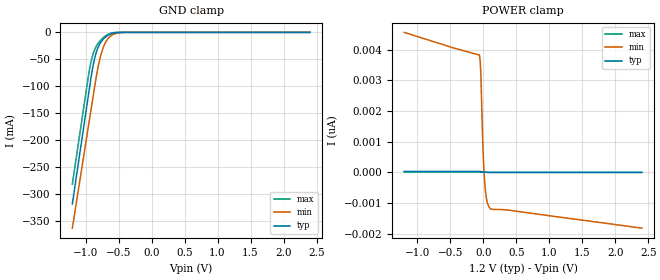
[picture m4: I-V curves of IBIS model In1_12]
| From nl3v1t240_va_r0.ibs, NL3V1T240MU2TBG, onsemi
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|//////////////////////////////////////////////////////////////////////////////
|//////////////////////////////////////////////////////////////////////////////
[Model]  In1_12
Model_type Input
Vinh =  0.84
Vinl =  0.36
|  variable   typ   min   max
C_comp   6.2pF   6.2pF   6.2pF
|//////////////////////////////////////////////////////////////////////////////
[Temperature Range]   25   125   -40
|//////////////////////////////////////////////////////////////////////////////
[Voltage Range]   1.20V   1.10V   1.30V
|//////////////////////////////////////////////////////////////////////////////
[POWER Clamp Reference] 1.20V   1.10V   1.30V
|//////////////////////////////////////////////////////////////////////////////
[GND Clamp Reference]   0V   0V   0V
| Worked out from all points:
|   GND clamp passes 1 mA (typ) near -0.56 V on its own axis
|//////////////////////////////////////////////////////////////////////////////
[GND Clamp]
|   Voltage   I(typ)   I(min)   I(max)
-1.2V     -318.7mA   -363.4mA   -282mA
-960mV    -119.4mA   -177.1mA   -83.84mA
-940mV    -102.8mA   -161.6mA   -69.07mA
-900mV    -71.2mA    -130.5mA   -46.37mA
-840mV    -38.28mA   -84.25mA   -26.43mA
-800mV    -25.17mA   -58.4mA    -18.78mA
-760mV    -16.85mA   -38.63mA   -13.12mA
-700mV    -9.037mA   -19.28mA   -6.774mA
-620mV    -3.033mA   -6.913mA   -1.801mA
-520mV    -307.5uA   -1.373mA   -95.74uA
-400mV    -4.681uA   -69.73uA   -655.5nA
2.4V      -8.2pA     -741.9pA   295.3fA
|//////////////////////////////////////////////////////////////////////////////
[POWER Clamp]
|   Voltage   I(typ)   I(min)   I(max)
-1.2V     26.79pA    4.56nA     366.4fA
-60mV     24.69pA    3.819nA    -443.2fA
-50mV     22.92pA    3.653nA    -450.3fA
-40mV     20.39pA    3.239nA    -457.4fA
-10mV     10.81pA    961.7pA    -478.7fA
0V        7.579pA    411.5pA    -485.8fA
20mV      1.714pA    -336.9pA   -500fA
30mV      -662.3fA   -600pA     -507.1fA
50mV      -4.24pA    -908.4pA   -521.3fA
80mV      -6.995pA   -1.116nA   -542.6fA
110mV     -7.838pA   -1.194nA   -563.9fA
2.4V      -9.735pA   -1.823nA   -2.19pA
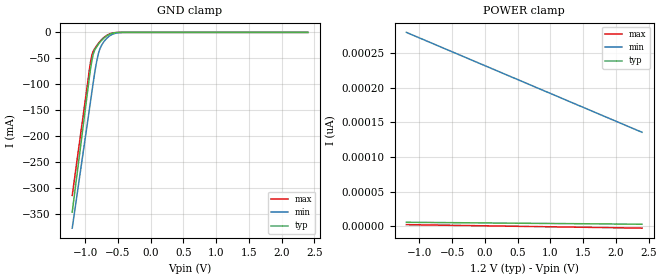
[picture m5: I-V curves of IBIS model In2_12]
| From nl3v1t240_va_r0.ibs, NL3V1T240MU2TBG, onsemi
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|//////////////////////////////////////////////////////////////////////////////
|//////////////////////////////////////////////////////////////////////////////
[Model]  In2_12
Model_type Input
Vinh =  0.84
Vinl =  0.36
|  variable   typ   min   max
C_comp   4.8pF   4.8pF   4.8pF
|//////////////////////////////////////////////////////////////////////////////
[Temperature Range]   25   125   -40
|//////////////////////////////////////////////////////////////////////////////
[Voltage Range]   1.20V   1.10V   1.30V
|//////////////////////////////////////////////////////////////////////////////
[POWER Clamp Reference] 1.20V   1.10V   1.30V
|//////////////////////////////////////////////////////////////////////////////
[GND Clamp Reference]   0V   0V   0V
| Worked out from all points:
|   GND clamp passes 1 mA (typ) near -0.56 V on its own axis
|//////////////////////////////////////////////////////////////////////////////
[GND Clamp]
|   Voltage   I(typ)   I(min)   I(max)
-1.2V     -346.3mA   -377.1mA   -314mA
-940mV    -88.24mA   -150mA     -73.73mA
-900mV    -54.32mA   -115.1mA   -44.15mA
-880mV    -42.51mA   -97.64mA   -36.66mA
-860mV    -35.19mA   -80.63mA   -32.16mA
-820mV    -26.61mA   -51.9mA    -24.64mA
-800mV    -22.96mA   -40.82mA   -21.17mA
-740mV    -13.75mA   -22.38mA   -12.56mA
-660mV    -5.672mA   -9.946mA   -4.966mA
-560mV    -947.3uA   -2.507mA   -706.6uA
-420mV    -10.83uA   -97.89uA   -5.741uA
2.4V      5.63pA     284.2pA    2.062pA
|//////////////////////////////////////////////////////////////////////////////
[POWER Clamp]
|   Voltage   I(typ)   I(min)   I(max)
-1.2V     5.63pA     280.2pA    2.202pA
0V        4.688pA    232pA      525.4fA
1.2V      3.745pA    183.9pA    -1.151pA
2.4V      2.803pA    135.8pA    -2.828pA
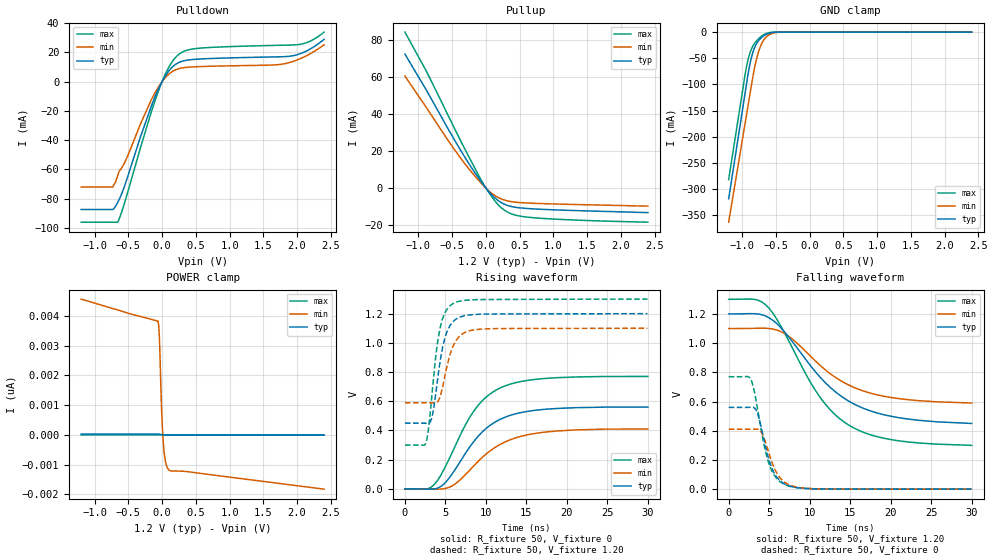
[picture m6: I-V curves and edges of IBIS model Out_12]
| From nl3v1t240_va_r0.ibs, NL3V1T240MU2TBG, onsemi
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|//////////////////////////////////////////////////////////////////////////////
|//////////////////////////////////////////////////////////////////////////////
[Model] Out_12
Model_type 3-state
Polarity Inverting
Enable Active-Low
Vmeas = 0.6
Vref = 1.2
Rref = 2k
Cref = 15pF
|  variable   typ   min   max
C_comp   5.9pF   5.9pF   5.9pF
|//////////////////////////////////////////////////////////////////////////////
[Temperature Range]   25   125   -40
|//////////////////////////////////////////////////////////////////////////////
[Voltage Range]   1.20V   1.10V   1.30V
|//////////////////////////////////////////////////////////////////////////////
[Pulldown Reference]   0V   0V   0V
|//////////////////////////////////////////////////////////////////////////////
[Pullup Reference]   1.20V   1.10V   1.30V
|//////////////////////////////////////////////////////////////////////////////
[GND Clamp Reference]   0V   0V   0V
|//////////////////////////////////////////////////////////////////////////////
[POWER Clamp Reference] 1.20V   1.10V   1.30V
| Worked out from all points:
|   slope of the pulldown table from 0 to 0.18 V, typ, clamps not added: 16.2 ohm
|   slope of the pullup table from 0 to 0.18 V, typ, clamps not added: 26.9 ohm
|   GND clamp passes 1 mA (typ) near -0.56 V on its own axis
|   falling waveform, R_fixture 50, V_fixture 1.20: 20-80 % time 7.63ns typ, 7.21ns min, 6.75ns max; typ from 1.2 V to 0.45 V
|   falling waveform, R_fixture 50, V_fixture 0: 20-80 % time 1.69ns typ, 1.77ns min, 1.76ns max; typ from 0.56 V to 0 V
|   rising waveform, R_fixture 50, V_fixture 0: 20-80 % time 4.92ns typ, 5.45ns min, 4.78ns max; typ from 0 V to 0.56 V
|   rising waveform, R_fixture 50, V_fixture 1.20: 20-80 % time 1.36ns typ, 1.5ns min, 1.26ns max; typ from 0.45 V to 1.2 V
|//////////////////////////////////////////////////////////////////////////////
[Pulldown]
|   Voltage   I(typ)   I(min)   I(max)
-1.2V     -87.41mA   -72.09mA   -96.08mA
-730mV    -87.41mA   -72.09mA   -96.08mA
-650mV    -81.85mA   -63.15mA   -95.35mA
-540mV    -69.07mA   -53.8mA    -80.31mA
-320mV    -37.64mA   -28.83mA   -45.04mA
-100mV    -9.841mA   -7.212mA   -12.32mA
80mV      6.064mA    4.222mA    8.144mA
240mV     12.83mA    8.647mA    18.27mA
560mV     15.37mA    10.18mA    22.77mA
1.77V     16.92mA    11.8mA     24.76mA
2.13V     20.64mA    17.39mA    26.37mA
2.4V      28.8mA     25.07mA    33.75mA
|//////////////////////////////////////////////////////////////////////////////
[Pullup]
|   Voltage   I(typ)   I(min)   I(max)
-1.2V     72.38mA    60.55mA    84.3mA
-880mV    52.83mA    43.38mA    63.02mA
-550mV    31.34mA    25.21mA    38.52mA
-280mV    14.85mA    11.69mA    18.83mA
-100mV    4.991mA    3.89mA     6.334mA
0V        8.022uA    5.575uA    19.24uA
120mV     -4.891mA   -3.724mA   -6.292mA
240mV     -8.095mA   -6.041mA   -11mA
400mV     -10.15mA   -7.447mA   -14.22mA
660mV     -11.15mA   -8.14mA    -15.88mA
1.37V     -12.21mA   -8.924mA   -17.35mA
2.4V      -13.25mA   -9.76mA    -18.44mA
|//////////////////////////////////////////////////////////////////////////////
[GND Clamp]
|   Voltage   I(typ)   I(min)   I(max)
-1.2V     -318.7mA   -363.4mA   -282mA
-960mV    -119.4mA   -177.1mA   -83.84mA
-940mV    -102.8mA   -161.6mA   -69.07mA
-900mV    -71.2mA    -130.5mA   -46.37mA
-840mV    -38.28mA   -84.25mA   -26.43mA
-800mV    -25.17mA   -58.4mA    -18.78mA
-760mV    -16.85mA   -38.63mA   -13.12mA
-700mV    -9.037mA   -19.28mA   -6.774mA
-620mV    -3.033mA   -6.913mA   -1.801mA
-520mV    -307.5uA   -1.373mA   -95.74uA
-400mV    -4.681uA   -69.73uA   -655.5nA
2.4V      -8.2pA     -741.9pA   295.3fA
|//////////////////////////////////////////////////////////////////////////////
[POWER Clamp]
|   Voltage   I(typ)   I(min)   I(max)
-1.2V     26.79pA    4.56nA     366.4fA
-60mV     24.69pA    3.819nA    -443.2fA
-50mV     22.92pA    3.653nA    -450.3fA
-40mV     20.39pA    3.239nA    -457.4fA
-10mV     10.81pA    961.7pA    -478.7fA
0V        7.579pA    411.5pA    -485.8fA
20mV      1.714pA    -336.9pA   -500fA
30mV      -662.3fA   -600pA     -507.1fA
50mV      -4.24pA    -908.4pA   -521.3fA
80mV      -6.995pA   -1.116nA   -542.6fA
110mV     -7.838pA   -1.194nA   -563.9fA
2.4V      -9.735pA   -1.823nA   -2.19pA
|//////////////////////////////////////////////////////////////////////////////
|//////////////////////////////////////////////////////////////////////////////
[Ramp]
|  variable   typ   min   max
dV/dt_r   3.360E-01/4.950E-09  2.460E-01/5.550E-09  4.620E-01/4.800E-09
dV/dt_f   4.500E-01/7.600E-09  3.060E-01/7.200E-09  6.000E-01/6.600E-09
R_load = 50
|//////////////////////////////////////////////////////////////////////////////
[Falling Waveform]
R_fixture = 50
V_fixture = 1.20
V_fixture_min = 1.10
V_fixture_max = 1.30
C_fixture = 0p
|   time   V(typ)   V(min)   V(max)
0s        1.2V       1.1V       1.3V
3.2ns     1.201V     1.101V     1.3V
4.8ns     1.179V     1.101V     1.25V
7.2ns     1.057V     1.055V     1.039V
11ns      785.3mV    862.9mV    652.4mV
12.8ns    684.6mV    780.5mV    528.9mV
14.8ns    604.1mV    713.9mV    440.1mV
17.2ns    541.9mV    662.7mV    378.3mV
20.15ns   498mV      626.9mV    338.5mV
30ns      450mV      590mV      300mV
|//////////////////////////////////////////////////////////////////////////////
[Falling Waveform]
R_fixture = 50
V_fixture = 0
C_fixture = 0p
|   time   V(typ)   V(min)   V(max)
0s        560mV      410mV      770mV
2.7ns     560.8mV    410mV      754.7mV
3.1ns     558.9mV    410.5mV    685.6mV
3.6ns     513.5mV    410.2mV    539.6mV
4.2ns     378.6mV    373.5mV    349.8mV
4.9ns     215.5mV    259.1mV    187.4mV
5.8ns     93.78mV    125.1mV    82.49mV
6.9ns     35.55mV    48.27mV    32.77mV
10.5ns    2.628mV    3.42mV     2.699mV
30ns      0V         0V         0V
|//////////////////////////////////////////////////////////////////////////////
[Rising Waveform]
R_fixture = 50
V_fixture = 0
C_fixture = 0p
|   time   V(typ)   V(min)   V(max)
0s        0V         0V         0V
2.7ns     -1.551mV   -625.2uV   -50.82uV
3.6ns     -802.5uV   -1.563mV   29.01mV
5.25ns    59.36mV    6.816mV    181.5mV
6.45ns    154.1mV    44.54mV    322.7mV
8.4ns     316.9mV    151.3mV    523.7mV
10.05ns   414.7mV    239.5mV    629.4mV
11.85ns   478.4mV    307mV      693.1mV
17.15ns   544.3mV    387.9mV    755.6mV
30ns      560mV      410mV      770mV
|//////////////////////////////////////////////////////////////////////////////
[Rising Waveform]
R_fixture = 50
V_fixture = 1.20
V_fixture_min = 1.10
V_fixture_max = 1.30
C_fixture = 0p
|   time   V(typ)   V(min)   V(max)
0s        450mV      590mV      300mV
2.6ns     449.5mV    590mV      316mV
2.9ns     448.6mV    590mV      407.8mV
3.4ns     506.4mV    589.5mV    681.8mV
4.3ns     855.7mV    624.8mV    1.089V
5ns       1.045V     789.3mV    1.212V
5.9ns     1.143V     971.2mV    1.267V
7.1ns     1.182V     1.061V     1.289V
9.1ns     1.196V     1.093V     1.296V
29.95ns   1.2V       1.1V       1.3V
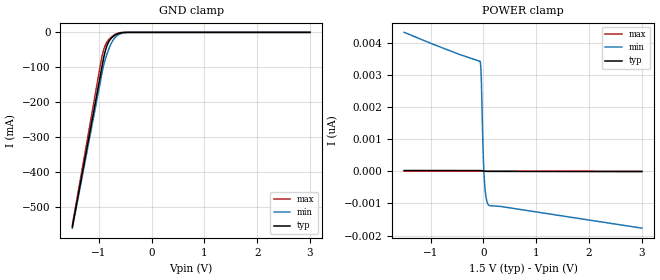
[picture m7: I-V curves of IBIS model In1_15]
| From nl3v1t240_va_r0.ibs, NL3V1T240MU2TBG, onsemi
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|//////////////////////////////////////////////////////////////////////////////
|//////////////////////////////////////////////////////////////////////////////
[Model]  In1_15
Model_type Input
Vinh =  1.05
Vinl =  0.45
|  variable   typ   min   max
C_comp   6.2pF   6.2pF   6.2pF
|//////////////////////////////////////////////////////////////////////////////
[Temperature Range]   25   125   -40
|//////////////////////////////////////////////////////////////////////////////
[Voltage Range]   1.50V   1.40V   1.60V
|//////////////////////////////////////////////////////////////////////////////
[POWER Clamp Reference] 1.50V   1.40V   1.60V
|//////////////////////////////////////////////////////////////////////////////
[GND Clamp Reference]   0V   0V   0V
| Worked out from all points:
|   GND clamp passes 1 mA (typ) near -0.57 V on its own axis
|//////////////////////////////////////////////////////////////////////////////
[GND Clamp]
|   Voltage   I(typ)   I(min)   I(max)
-1.5V     -557.7mA   -561.1mA   -552.3mA
-960mV    -115.9mA   -134.5mA   -85.51mA
-940mV    -99.49mA   -118.7mA   -70.19mA
-900mV    -68.21mA   -89.65mA   -46.72mA
-860mV    -44.98mA   -69.53mA   -31.68mA
-800mV    -24.14mA   -44mA      -18.84mA
-740mV    -13.37mA   -25.16mA   -10.78mA
-680mV    -6.942mA   -13.11mA   -5.168mA
-620mV    -2.923mA   -6.276mA   -1.797mA
-460mV    -38.74uA   -327.3uA   -8.324uA
3V        -107.2fA   -626.2pA   1.119pA
|//////////////////////////////////////////////////////////////////////////////
[POWER Clamp]
|   Voltage   I(typ)   I(min)   I(max)
-1.5V     21.77pA    4.316nA    1.167pA
-60mV     19.08pA    3.413nA    484.2fA
-50mV     18.75pA    3.259nA    479.4fA
-40mV     17.79pA    2.878nA    474.7fA
-10mV     10.26pA    822.4pA    460.4fA
0V        7.334pA    334.5pA    455.7fA
10mV      4.593pA    -46.06pA   451fA
20mV      2.157pA    -327pA     446.2fA
30mV      85.95fA    -556.4pA   441.5fA
50mV      -2.83pA    -815.8pA   432fA
100mV     -4.914pA   -1.057nA   408.3fA
3V        -13.66pA   -1.77nA    -966.4fA
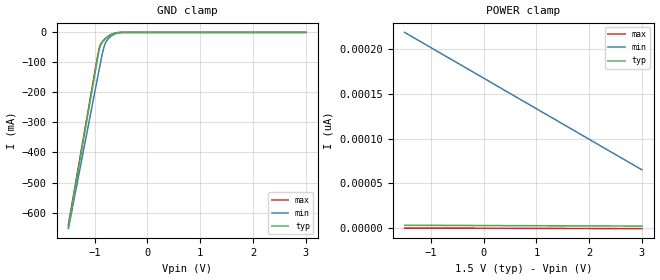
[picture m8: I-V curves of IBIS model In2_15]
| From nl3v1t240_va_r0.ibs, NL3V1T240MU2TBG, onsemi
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|//////////////////////////////////////////////////////////////////////////////
|//////////////////////////////////////////////////////////////////////////////
[Model]  In2_15
Model_type Input
Vinh =  1.05
Vinl =  0.45
|  variable   typ   min   max
C_comp   4.8pF   4.8pF   4.8pF
|//////////////////////////////////////////////////////////////////////////////
[Temperature Range]   25   125   -40
|//////////////////////////////////////////////////////////////////////////////
[Voltage Range]   1.50V   1.40V   1.60V
|//////////////////////////////////////////////////////////////////////////////
[POWER Clamp Reference] 1.50V   1.40V   1.60V
|//////////////////////////////////////////////////////////////////////////////
[GND Clamp Reference]   0V   0V   0V
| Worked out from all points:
|   GND clamp passes 1 mA (typ) near -0.57 V on its own axis
|//////////////////////////////////////////////////////////////////////////////
[GND Clamp]
|   Voltage   I(typ)   I(min)   I(max)
-1.5V     -647.1mA   -653.7mA   -640.7mA
-960mV    -99.94mA   -163.4mA   -92.65mA
-920mV    -62.15mA   -127.1mA   -55.93mA
-900mV    -47.82mA   -108.9mA   -43.57mA
-880mV    -38.63mA   -90.77mA   -36.45mA
-840mV    -29.17mA   -58.76mA   -28.07mA
-800mV    -21.77mA   -36.39mA   -20.87mA
-760mV    -15.56mA   -24.65mA   -14.88mA
-640mV    -3.867mA   -7.053mA   -3.566mA
-460mV    -31.96uA   -229.2uA   -24.55uA
3V        3.178pA    222.1pA    38.72fA
|//////////////////////////////////////////////////////////////////////////////
[POWER Clamp]
|   Voltage   I(typ)   I(min)   I(max)
-1.5V     3.178pA    218.7pA    53.57fA
0V        2.87pA     167.5pA    -169.2fA
1.5V      2.562pA    116.3pA    -392fA
3V        2.255pA    65.13pA    -614.8fA
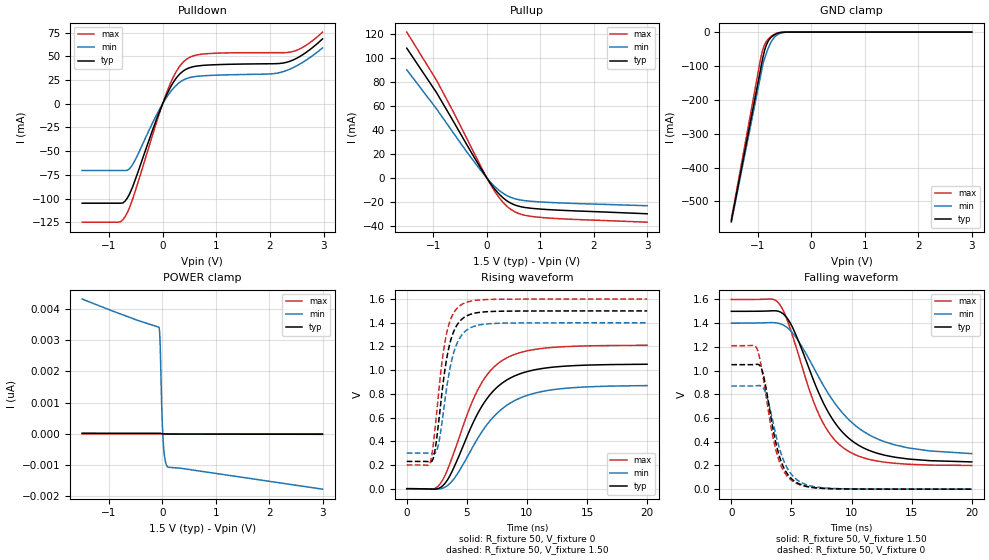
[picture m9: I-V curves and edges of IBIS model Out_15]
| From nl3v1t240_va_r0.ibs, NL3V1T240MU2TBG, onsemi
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|//////////////////////////////////////////////////////////////////////////////
|//////////////////////////////////////////////////////////////////////////////
[Model] Out_15
Model_type 3-state
Polarity Inverting
Enable Active-Low
Vmeas = 0.75
Vref = 1.5
Rref = 2k
Cref = 15pF
|  variable   typ   min   max
C_comp   5.9pF   5.9pF   5.9pF
|//////////////////////////////////////////////////////////////////////////////
[Temperature Range]   25   125   -40
|//////////////////////////////////////////////////////////////////////////////
[Voltage Range]   1.50V   1.40V   1.60V
|//////////////////////////////////////////////////////////////////////////////
[Pulldown Reference]   0V   0V   0V
|//////////////////////////////////////////////////////////////////////////////
[Pullup Reference]   1.50V   1.40V   1.60V
|//////////////////////////////////////////////////////////////////////////////
[GND Clamp Reference]   0V   0V   0V
|//////////////////////////////////////////////////////////////////////////////
[POWER Clamp Reference] 1.50V   1.40V   1.60V
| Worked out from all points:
|   slope of the pulldown table from 0 to 0.225 V, typ, clamps not added: 9.08 ohm
|   slope of the pullup table from 0 to 0.225 V, typ, clamps not added: 17 ohm
|   GND clamp passes 1 mA (typ) near -0.57 V on its own axis
|   falling waveform, R_fixture 50, V_fixture 1.50: 20-80 % time 3.62ns typ, 4.53ns min, 3.09ns max; typ from 1.5 V to 0.23 V
|   falling waveform, R_fixture 50, V_fixture 0: 20-80 % time 1.33ns typ, 1.5ns min, 1.36ns max; typ from 1.05 V to 0 V
|   rising waveform, R_fixture 50, V_fixture 0: 20-80 % time 3.29ns typ, 3.71ns min, 3.04ns max; typ from 0 V to 1.05 V
|   rising waveform, R_fixture 50, V_fixture 1.50: 20-80 % time 1.08ns typ, 1.13ns min, 1.01ns max; typ from 0.23 V to 1.5 V
|//////////////////////////////////////////////////////////////////////////////
[Pulldown]
|   Voltage   I(typ)   I(min)   I(max)
-1.5V     -104.7mA   -70.31mA   -124.7mA
-820mV    -104.7mA   -70.31mA   -124.7mA
-700mV    -102.6mA   -70.31mA   -119mA
-560mV    -87.62mA   -64.15mA   -100.5mA
-100mV    -14.22mA   -10.23mA   -16.98mA
90mV      11.26mA    8.129mA    13.93mA
270mV     28.22mA    20.34mA    35.49mA
420mV     35.82mA    25.95mA    45.78mA
810mV     40.64mA    29.63mA    52.67mA
2.28V     43.27mA    34.47mA    53.82mA
2.58V     50.58mA    42.58mA    58.51mA
2.98V     68.35mA    58.85mA    75.48mA
|//////////////////////////////////////////////////////////////////////////////
[Pullup]
|   Voltage   I(typ)   I(min)   I(max)
-1.5V     108.2mA    90.16mA    121.6mA
-940mV    70.95mA    57.42mA    81.26mA
-630mV    47.38mA    37.72mA    55.25mA
-300mV    21.93mA    17.15mA    26.13mA
40mV      -2.764mA   -2.134mA   -3.163mA
220mV     -13.02mA   -10.05mA   -15.9mA
320mV     -17.24mA   -13.26mA   -21.19mA
410mV     -20.09mA   -15.45mA   -24.92mA
510mV     -22.31mA   -17.15mA   -27.9mA
620mV     -23.83mA   -18.32mA   -30.02mA
930mV     -25.71mA   -19.81mA   -32.59mA
3V        -29.87mA   -23.17mA   -36.9mA
|//////////////////////////////////////////////////////////////////////////////
[GND Clamp]
|   Voltage   I(typ)   I(min)   I(max)
-1.5V     -557.7mA   -561.1mA   -552.3mA
-960mV    -115.9mA   -134.5mA   -85.51mA
-940mV    -99.49mA   -118.7mA   -70.19mA
-900mV    -68.21mA   -89.65mA   -46.72mA
-860mV    -44.98mA   -69.53mA   -31.68mA
-800mV    -24.14mA   -44mA      -18.84mA
-740mV    -13.37mA   -25.16mA   -10.78mA
-680mV    -6.942mA   -13.11mA   -5.168mA
-620mV    -2.923mA   -6.276mA   -1.797mA
-460mV    -38.74uA   -327.3uA   -8.324uA
3V        -107.2fA   -626.2pA   1.119pA
|//////////////////////////////////////////////////////////////////////////////
[POWER Clamp]
|   Voltage   I(typ)   I(min)   I(max)
-1.5V     21.77pA    4.316nA    1.167pA
-60mV     19.08pA    3.413nA    484.2fA
-50mV     18.75pA    3.259nA    479.4fA
-40mV     17.79pA    2.878nA    474.7fA
-10mV     10.26pA    822.4pA    460.4fA
0V        7.334pA    334.5pA    455.7fA
10mV      4.593pA    -46.06pA   451fA
20mV      2.157pA    -327pA     446.2fA
30mV      85.95fA    -556.4pA   441.5fA
50mV      -2.83pA    -815.8pA   432fA
100mV     -4.914pA   -1.057nA   408.3fA
3V        -13.66pA   -1.77nA    -966.4fA
|//////////////////////////////////////////////////////////////////////////////
|//////////////////////////////////////////////////////////////////////////////
[Ramp]
|  variable   typ   min   max
dV/dt_r   6.300E-01/3.250E-09  5.220E-01/3.625E-09  7.260E-01/3.000E-09
dV/dt_f   7.620E-01/3.700E-09  6.600E-01/4.500E-09  8.400E-01/3.100E-09
R_load = 50
|//////////////////////////////////////////////////////////////////////////////
[Falling Waveform]
R_fixture = 50
V_fixture = 1.50
V_fixture_min = 1.40
V_fixture_max = 1.60
C_fixture = 0p
|   time   V(typ)   V(min)   V(max)
0s        1.5V       1.4V       1.6V
3.3ns     1.504V     1.405V     1.603V
4ns       1.497V     1.397V     1.561V
5.1ns     1.362V     1.317V     1.291V
7.3ns     805.5mV    939.5mV    626.9mV
8.3ns     609mV      770.2mV    452.3mV
9.5ns     454.5mV    614.9mV    335.6mV
11.3ns    333.8mV    467.8mV    255.9mV
13.58ns   269.9mV    374.1mV    218.5mV
20ns      230mV      300mV      200mV
|//////////////////////////////////////////////////////////////////////////////
[Falling Waveform]
R_fixture = 50
V_fixture = 0
C_fixture = 0p
|   time   V(typ)   V(min)   V(max)
0s        1.05V      870mV      1.21V
2.1ns     1.053V     871.9mV    1.192V
2.4ns     1.039V     873mV      1.085V
2.7ns     948mV      847.3mV    908.7mV
3.3ns     604.1mV    641.2mV    524.6mV
3.8ns     350.1mV    419mV      294.7mV
4.4ns     173.4mV    230mV      145.6mV
5.2ns     71.11mV    102.3mV    60.83mV
8ns       5.333mV    8.714mV    4.802mV
20ns      0V         0V         0V
|//////////////////////////////////////////////////////////////////////////////
[Rising Waveform]
R_fixture = 50
V_fixture = 0
C_fixture = 0p
|   time   V(typ)   V(min)   V(max)
0s        0V         0V         0V
2.125ns   -3.906mV   -3.482mV   -2.481mV
2.75ns    7.306mV    -1.388mV   37.35mV
3.875ns   168.2mV    76.61mV    290.9mV
5.875ns   628.9mV    419.7mV    827.3mV
6.875ns   786.5mV    566.1mV    985.3mV
8.125ns   904.3mV    689.2mV    1.093V
9.75ns    980.4mV    777.7mV    1.157V
12ns      1.024V     832.9mV    1.191V
20ns      1.05V      870mV      1.21V
|//////////////////////////////////////////////////////////////////////////////
[Rising Waveform]
R_fixture = 50
V_fixture = 1.50
V_fixture_min = 1.40
V_fixture_max = 1.60
C_fixture = 0p
|   time   V(typ)   V(min)   V(max)
0s        230mV      300mV      200mV
1.95ns    226mV      298.9mV    220.5mV
2.25ns    273.2mV    295.5mV    408.2mV
2.6ns     514.6mV    356.4mV    754.4mV
2.95ns    828.2mV    572.4mV    1.083V
3.25ns    1.053V     800.5mV    1.278V
3.8ns     1.298V     1.108V     1.464V
4.5ns     1.422V     1.285V     1.55V
6.8ns     1.494V     1.391V     1.596V
20ns      1.5V       1.4V       1.6V
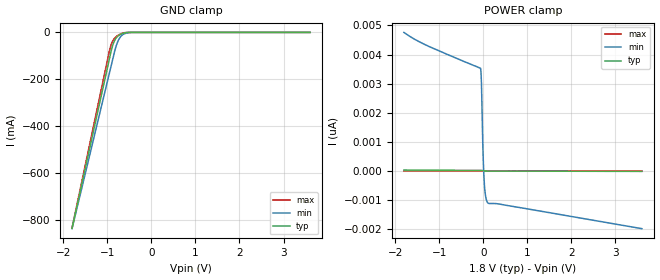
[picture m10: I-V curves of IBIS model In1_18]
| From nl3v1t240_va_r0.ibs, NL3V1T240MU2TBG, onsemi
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|//////////////////////////////////////////////////////////////////////////////
|//////////////////////////////////////////////////////////////////////////////
[Model]  In1_18
Model_type Input
Vinh =  1.17
Vinl =  0.63
|  variable   typ   min   max
C_comp   6.2pF   6.2pF   6.2pF
|//////////////////////////////////////////////////////////////////////////////
[Temperature Range]   25   125   -40
|//////////////////////////////////////////////////////////////////////////////
[Voltage Range]   1.80V   1.65V   1.95V
|//////////////////////////////////////////////////////////////////////////////
[POWER Clamp Reference] 1.80V   1.65V   1.95V
|//////////////////////////////////////////////////////////////////////////////
[GND Clamp Reference]   0V   0V   0V
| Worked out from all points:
|   GND clamp passes 1 mA (typ) near -0.57 V on its own axis
|//////////////////////////////////////////////////////////////////////////////
[GND Clamp]
|   Voltage   I(typ)   I(min)   I(max)
-1.8V     -834.6mA   -836.2mA   -832.7mA
-960mV    -119.4mA   -179.5mA   -85.23mA
-920mV    -85.38mA   -148.3mA   -56.63mA
-880mV    -56.94mA   -117mA     -37.69mA
-840mV    -37.08mA   -85.74mA   -26.12mA
-800mV    -24.33mA   -58.65mA   -18.59mA
-740mV    -13.37mA   -30.44mA   -10.6mA
-680mV    -6.897mA   -14.63mA   -5.041mA
-600mV    -2.006mA   -5.032mA   -1.087mA
-480mV    -76.25uA   -545.6uA   -17.52uA
3.6V      182.4fA    -559.8pA   2.202pA
|//////////////////////////////////////////////////////////////////////////////
[POWER Clamp]
|   Voltage   I(typ)   I(min)   I(max)
-1.8V     30.61pA    4.763nA    2.297pA
-1.24V    24.24pA    4.285nA    1.941pA
-60mV     16.09pA    3.529nA    1.191pA
-50mV     16.02pA    3.381nA    1.184pA
-40mV     15.63pA    3.007nA    1.178pA
-10mV     9.965pA    918.7pA    1.159pA
0V        7.063pA    402.9pA    1.152pA
20mV      1.834pA    -305.7pA   1.14pA
40mV      -2.197pA   -716.1pA   1.127pA
60mV      -4.533pA   -920.1pA   1.114pA
110mV     -6.235pA   -1.11nA    1.082pA
3.6V      -17.98pA   -1.988nA   -1.138pA
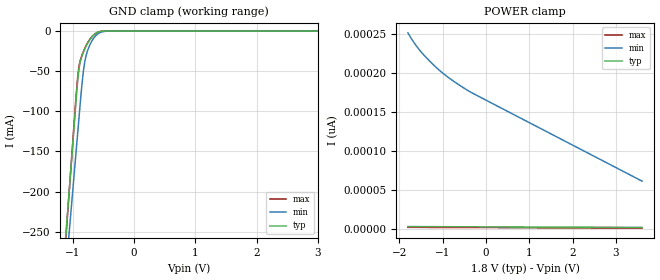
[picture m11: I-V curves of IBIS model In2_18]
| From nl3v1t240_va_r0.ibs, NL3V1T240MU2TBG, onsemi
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|//////////////////////////////////////////////////////////////////////////////
|//////////////////////////////////////////////////////////////////////////////
[Model]  In2_18
Model_type Input
Vinh =  1.17
Vinl =  0.63
|  variable   typ   min   max
C_comp   4.8pF   4.8pF   4.8pF
|//////////////////////////////////////////////////////////////////////////////
[Temperature Range]   25   125   -40
|//////////////////////////////////////////////////////////////////////////////
[Voltage Range]   1.80V   1.65V   1.95V
|//////////////////////////////////////////////////////////////////////////////
[POWER Clamp Reference] 1.80V   1.65V   1.95V
|//////////////////////////////////////////////////////////////////////////////
[GND Clamp Reference]   0V   0V   0V
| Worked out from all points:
|   GND clamp passes 1 mA (typ) near -0.57 V on its own axis
|//////////////////////////////////////////////////////////////////////////////
[GND Clamp]
|   Voltage   I(typ)   I(min)   I(max)
-1.8V     -949.2mA   -914.6mA   -991.5mA
-1.12V    -262.6mA   -306.9mA   -267.3mA
-1.06V    -202mA     -253.3mA   -203.4mA
-1.02V    -161.6mA   -217.5mA   -160.8mA
-940mV    -80.86mA   -146mA     -76.23mA
-900mV    -48.04mA   -110.3mA   -45.09mA
-840mV    -29.12mA   -59.69mA   -28.4mA
-800mV    -21.61mA   -36.85mA   -21.05mA
-720mV    -10.48mA   -17.13mA   -10.19mA
-620mV    -2.719mA   -5.469mA   -2.574mA
-400mV    -3.034uA   -39.27uA   -2.45uA
3.6V      3.12pA     221.3pA    2.156pA
|//////////////////////////////////////////////////////////////////////////////
[POWER Clamp]
|   Voltage   I(typ)   I(min)   I(max)
-1.8V     3.12pA     251.3pA    2.186pA
-1.68V    3.097pA    240.5pA    2.162pA
-1.56V    3.073pA    231.3pA    2.138pA
-1.42V    3.045pA    222.2pA    2.11pA
-1.24V    3.01pA     211.9pA    2.074pA
-900mV    2.942pA    195.6pA    2.005pA
-500mV    2.863pA    180.3pA    1.925pA
-220mV    2.808pA    171.5pA    1.868pA
3.6V      2.051pA    61.36pA    1.1pA
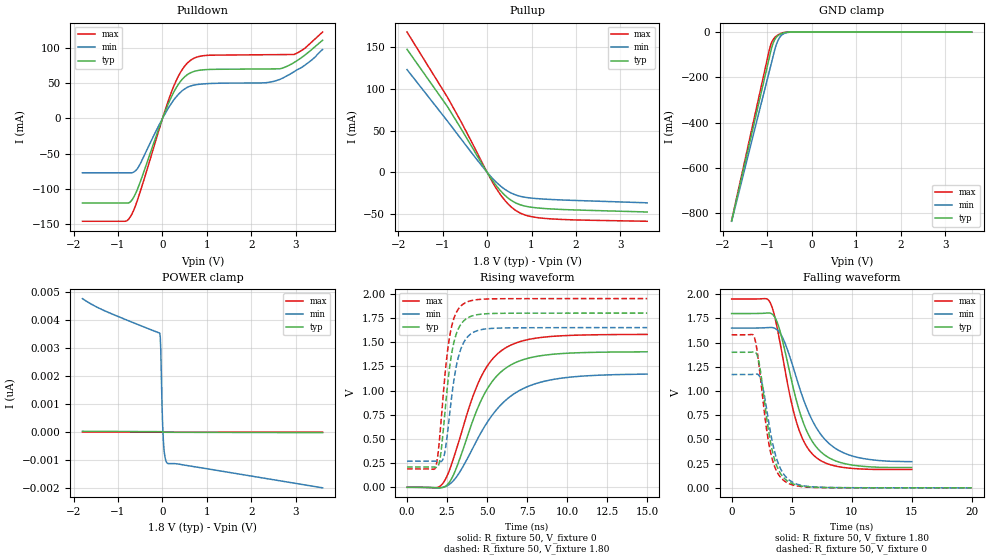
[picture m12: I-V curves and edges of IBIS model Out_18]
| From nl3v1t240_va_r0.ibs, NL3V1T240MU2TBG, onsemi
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|//////////////////////////////////////////////////////////////////////////////
|//////////////////////////////////////////////////////////////////////////////
[Model] Out_18
Model_type 3-state
Polarity Inverting
Enable Active-Low
Vmeas = 0.90
Vref = 1.8
Rref = 2k
Cref = 15pF
|  variable   typ   min   max
C_comp   5.9pF   5.9pF   5.9pF
|//////////////////////////////////////////////////////////////////////////////
[Temperature Range]   25   125   -40
|//////////////////////////////////////////////////////////////////////////////
[Voltage Range]   1.80V   1.65V   1.95V
|//////////////////////////////////////////////////////////////////////////////
[Pulldown Reference]   0V   0V   0V
|//////////////////////////////////////////////////////////////////////////////
[Pullup Reference]   1.80V   1.65V   1.95V
|//////////////////////////////////////////////////////////////////////////////
[GND Clamp Reference]   0V   0V   0V
|//////////////////////////////////////////////////////////////////////////////
[POWER Clamp Reference] 1.80V   1.65V   1.95V
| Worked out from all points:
|   slope of the pulldown table from 0 to 0.27 V, typ, clamps not added: 6.84 ohm
|   slope of the pullup table from 0 to 0.27 V, typ, clamps not added: 13.3 ohm
|   GND clamp passes 1 mA (typ) near -0.57 V on its own axis
|   falling waveform, R_fixture 50, V_fixture 1.80: 20-80 % time 2.18ns typ, 2.67ns min, 1.91ns max; typ from 1.8 V to 0.21 V
|   falling waveform, R_fixture 50, V_fixture 0: 20-80 % time 1.11ns typ, 1.19ns min, 1.06ns max; typ from 1.4 V to 0 V
|   rising waveform, R_fixture 50, V_fixture 0: 20-80 % time 2.19ns typ, 2.87ns min, 2.12ns max; typ from 0 V to 1.4 V
|   rising waveform, R_fixture 50, V_fixture 1.80: 20-80 % time 679ps typ, 738ps min, 653ps max; typ from 0.21 V to 1.8 V
|//////////////////////////////////////////////////////////////////////////////
[Pulldown]
|   Voltage   I(typ)   I(min)   I(max)
-1.8V     -120.5mA   -77.38mA   -146.5mA
-840mV    -120.5mA   -77.38mA   -146.5mA
-720mV    -118.7mA   -77.38mA   -139.9mA
-560mV    -100.4mA   -71.2mA    -115.8mA
-60mV     -10.33mA   -7.157mA   -12.3mA
200mV     30.7mA     21.46mA    37.41mA
400mV     52.48mA    37.02mA    65.3mA
600mV     64.09mA    45.58mA    81.38mA
1V        69.73mA    49.66mA    89.97mA
2.64V     70.76mA    55.72mA    NA
3.04V     83mA       69.85mA    93.73mA
3.6V      111.6mA    98.26mA    123.2mA
|//////////////////////////////////////////////////////////////////////////////
[Pullup]
|   Voltage   I(typ)   I(min)   I(max)
-1.8V     147.5mA    123.2mA    168.3mA
-890mV    78.67mA    61.33mA    89.9mA
-580mV    51.83mA    39.59mA    60.11mA
40mV      -3.416mA   -2.548mA   -3.964mA
190mV     -14.96mA   -11.14mA   -18.06mA
320mV     -23.34mA   -17.33mA   -28.36mA
440mV     -29.58mA   -21.93mA   -36.26mA
580mV     -35mA      -25.92mA   -43.37mA
720mV     -38.59mA   -28.54mA   -48.34mA
860mV     -40.76mA   -30.12mA   -51.49mA
1.26V     -43.47mA   -32.21mA   -55.28mA
3.6V      -47.77mA   -36.75mA   -58.91mA
|//////////////////////////////////////////////////////////////////////////////
[GND Clamp]
|   Voltage   I(typ)   I(min)   I(max)
-1.8V     -834.6mA   -836.2mA   -832.7mA
-960mV    -119.4mA   -179.5mA   -85.23mA
-920mV    -85.38mA   -148.3mA   -56.63mA
-880mV    -56.94mA   -117mA     -37.69mA
-840mV    -37.08mA   -85.74mA   -26.12mA
-800mV    -24.33mA   -58.65mA   -18.59mA
-740mV    -13.37mA   -30.44mA   -10.6mA
-680mV    -6.897mA   -14.63mA   -5.041mA
-600mV    -2.006mA   -5.032mA   -1.087mA
-480mV    -76.25uA   -545.6uA   -17.52uA
3.6V      182.4fA    -559.8pA   2.202pA
|//////////////////////////////////////////////////////////////////////////////
[POWER Clamp]
|   Voltage   I(typ)   I(min)   I(max)
-1.8V     30.61pA    4.763nA    2.297pA
-1.24V    24.24pA    4.285nA    1.941pA
-60mV     16.09pA    3.529nA    1.191pA
-50mV     16.02pA    3.381nA    1.184pA
-40mV     15.63pA    3.007nA    1.178pA
-10mV     9.965pA    918.7pA    1.159pA
0V        7.063pA    402.9pA    1.152pA
20mV      1.834pA    -305.7pA   1.14pA
40mV      -2.197pA   -716.1pA   1.127pA
60mV      -4.533pA   -920.1pA   1.114pA
110mV     -6.235pA   -1.11nA    1.082pA
3.6V      -17.98pA   -1.988nA   -1.138pA
|//////////////////////////////////////////////////////////////////////////////
|//////////////////////////////////////////////////////////////////////////////
[Ramp]
|  variable   typ   min   max
dV/dt_f   9.540E-01/2.100E-09  8.280E-01/2.700E-09  1.056E+00/1.900E-09
dV/dt_r   8.400E-01/2.200E-09  7.020E-01/2.900E-09  9.480E-01/2.100E-09
R_load = 50
|//////////////////////////////////////////////////////////////////////////////
[Falling Waveform]
R_fixture = 50
V_fixture = 1.80
V_fixture_min = 1.65
V_fixture_max = 1.95
C_fixture = 0p
|   time   V(typ)   V(min)   V(max)
0s        1.8V       1.65V      1.95V
3.2ns     1.804V     1.656V     1.916V
3.6ns     1.762V     1.647V     1.763V
4ns       1.633V     1.603V     1.52V
5.3ns     947.7mV    1.175V     722.7mV
6ns       663.5mV    907.4mV    483mV
6.8ns     463.9mV    677mV      340.4mV
8ns       318.5mV    471.2mV    248.1mV
9.5ns     247.9mV    352.6mV    207.5mV
15ns      210mV      270mV      190mV
|//////////////////////////////////////////////////////////////////////////////
[Falling Waveform]
R_fixture = 50
V_fixture = 0
C_fixture = 0p
|   time   V(typ)   V(min)   V(max)
0s        1.4V       1.17V      1.58V
1.9ns     1.404V     1.173V     1.552V
2.2ns     1.342V     1.171V     1.345V
2.5ns     1.121V     1.093V     1.03V
2.9ns     738.6mV    827mV      613.8mV
3.2ns     497.4mV    598.1mV    392.4mV
3.8ns     214.5mV    281.1mV    159.9mV
4.5ns     84.93mV    115.7mV    61.53mV
6.9ns     6.29mV     8.938mV    4.292mV
20ns      0V         0V         0V
|//////////////////////////////////////////////////////////////////////////////
[Rising Waveform]
R_fixture = 50
V_fixture = 0
C_fixture = 0p
|   time   V(typ)   V(min)   V(max)
0s        0V         0V         0V
1.8ns     -3.587mV   -5.211mV   -4.229mV
2.3ns     1.539mV    1.95mV     55.02mV
3ns       165.6mV    88.02mV    349.1mV
4.5ns     851.2mV    529mV      1.098V
5.2ns     1.066V     718.1mV    1.297V
6.1ns     1.223V     890.5mV    1.435V
7.4ns     1.326V     1.031V     1.521V
9ns       1.373V     1.111V     1.559V
15ns      1.4V       1.17V      1.58V
|//////////////////////////////////////////////////////////////////////////////
[Rising Waveform]
R_fixture = 50
V_fixture = 1.80
V_fixture_min = 1.65
V_fixture_max = 1.95
C_fixture = 0p
|   time   V(typ)   V(min)   V(max)
0s        210mV      270mV      190mV
1.8ns     206.2mV    269.8mV    213mV
2.1ns     336.2mV    264.7mV    633.3mV
2.35ns    741.2mV    353.6mV    1.124V
2.65ns    1.227V     736.9mV    1.547V
3.05ns    1.571V     1.227V     1.797V
3.5ns     1.713V     1.483V     1.893V
4.1ns     1.773V     1.598V     1.932V
5.1ns     1.795V     1.64V      1.947V
15ns      1.8V       1.65V      1.95V
